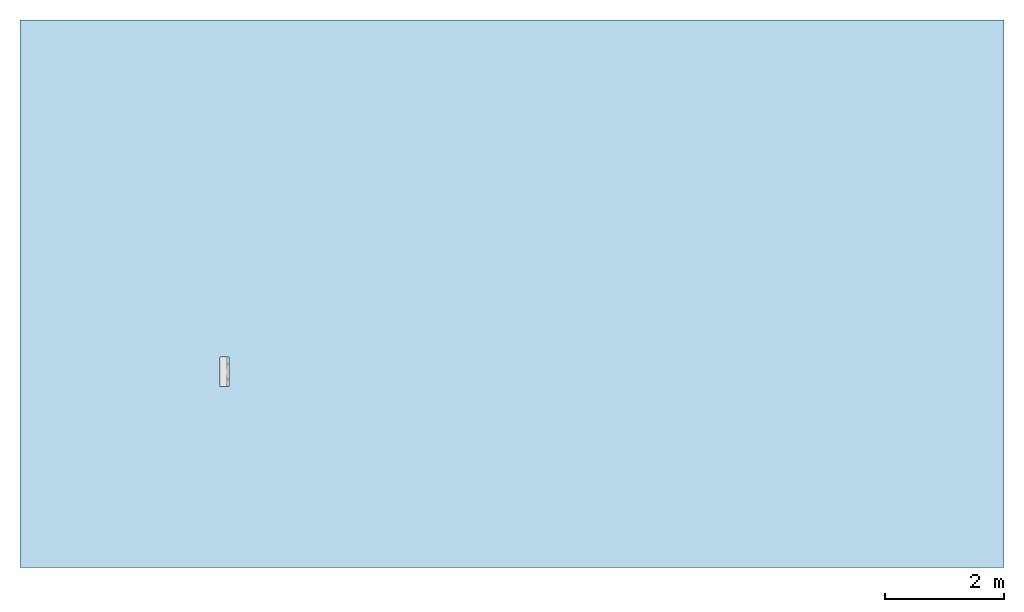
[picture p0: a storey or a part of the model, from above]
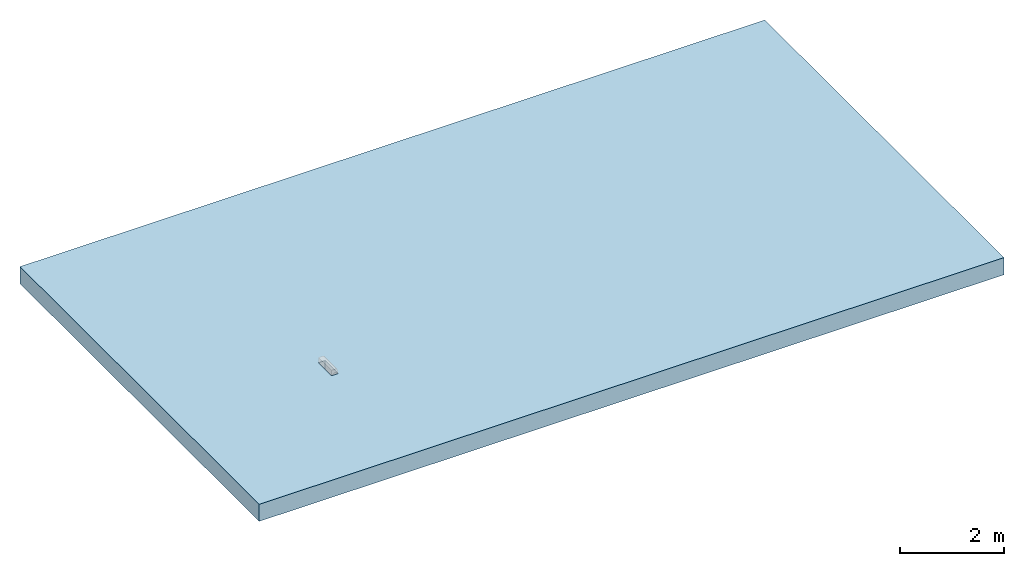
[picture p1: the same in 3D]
Properties of the parts of a building model (IFC2X3)

# File
Description: ViewDefinition [CoordinationView]
File name: 4231 - KDHB405 Channel - 500mm LG.ifc
Time: 2013-09-02T12:39:34
Written by: Autodesk Revit 2013
Made in: 20120221_2030(x64)

# IfcProject, Project Number
LongName: Project Name; Phase: Project Status

# IfcSite, Default
RefLatitude: 42, 21, 30, 344238; RefLongitude: -71, -3, -35, -194702; RefElevation: 0 mm

# IfcBuilding
Pset_BuildingCommon - NumberOfStoreys: 1
Other - Project Status: Project Status; Client Name: Owner; Project Number: Project Number; Project Address: ## Street City, State Zip; Project Name: Project Name; Project Issue Date: Issue Date

# IfcBuildingStorey, Level 1
LongName: Level 1; Elevation: 0 mm
Constraints - Elevation Base: 0; Elevation: 0 mm
Graphics - Line Pattern: Center; Symbol at End 2 Default: yes; Symbol: M_Level Head - Circle: M_Level Head - Circle; Color: 0; Line Weight: 1; Symbol at End 1 Default: no
Identity Data - Name: Level 1; Structural: no; Building Story: yes
Dimensions - Computation Height: 0 mm

# IfcBuildingElementProxy: 4231 - KDHB405 Channel - 500mm LG, Civil-Drainage-Channel-ACO-KerbDrain-HB405:4231 - KDHB405 Channel - 500mm LG:4231 - KDHB405 Channel - 500mm LG:312781
In: Level 1
Material: ACO Polymer Concrete.
Constraints - Level: Level: Level 1; Moves With Nearby Elements: no
Dimensions - Volume: 15413123 mm3; Void Width: 150 mm; Void Depth: -280 mm; Void Length: 500 mm; Circular Void Depth: 2000 mm
Phasing - Phase Created: New Construction
Pset_BuildingElementProxyCommon - Reference: 4231 - KDHB405 Channel - 500mm LG
Identity Data - e-mail Technical: technical@aco.co.uk; Model Description: Combined kerb and drainage system; Address: ACO Business Park, Hitchin Road, Shefford, Bedfordshire, United Kingdom SG17 5TE; Product Code: 4231; Product Page URL: http://www.aco.co.uk/product_detail.php?id=3; Assembly Description: Rain Water Drainage; Product brochure: http://www.aco.co.uk/download.php?id=120; Price: POA - contact ACO; Maintenance guidelines: http://www.aco.co.uk/download.php?id=120; Installation guidelines: http://www.aco.co.uk/download.php?id=120; URL: www.aco.co.uk; Type Comments: ACO KerbDrain HB405 half battered kerb unit 500mm long; Cost: 0; OmniClass Title: Rainwater Removal; Manufacturer: ACO Technologies plc - ACO Water Management Division; OmniClass Number: 23.70.50.24; e-mail Sales: customersupport@aco.co.uk; Telephone: +44 (0)1462 816666; Model: ACO KerbDrain HB405; Fax: +44 (0)1462 815895; Assembly Code: D2040
Construction - HB405 500_blindunit: no; RH drop kerb: no; LH drop kerb: no; Closing end cap: no; LH inlet/outlet end cap: no; RH inlet/outlet end cap: no; Access Unit: no; HB405 - 1000: no; HB405 - 500: yes; Centre Stone: no
Green Building Properties - Channel Recyclable: Fully recyclable; End Cap Recycled Material Content: N/A; Channel Recycled Material Content: 20% minimum; Access Cover/Frame Recycled Material Content: N/A; Access Cover/Frame Recyclable: N/A; End Cap Recyclable: N/A
General - SerialNumber: 0.000000; TagNumber: 0.000000
Materials and Finishes - Channel Colour: Grey; End Cap Colour: N/A; End Cap Material: N/A; Access Cover/Frame Finish: N/A; Connection Pipe Material: N/A; Channel Material: Vienite® Synthetic Resin Concrete; Access Cover/Frame Material: N/A; Connection Pipe Material Colour: N/A; Access Cover/Frame Colour: N/A
Data - Drainage Slot Intake area: 14592mm²/m; Product Dimensions: 500mm x 150mm x 405mm (LxWxH); Hydraulic Performance: http://www.aco.co.uk/download.php?id=120; Invert Depth: 380mm; Channel C.S.A: 0.03m²; Product Weight: 30.9 kg; Connection Pipe O.D: N/A; Concrete Surround Volume - Load Class A 15 - D 400 - Concrete Pavement: 0.17m³/m; Load Class: A 15 - D 400 A 15 - D 400; Drainage Slot Width: 50mm; Concrete Surround Volume - Load Class A 15 - D 400 - Grass or Asphalt Pavement: 0.16m³/m; ACO Hydraulic Design Software: http://www.acodesign.co.uk; Installation - Concrete Grade: Refer to brochure; Product Standard: BS EN 1433:2002, CE marked, Kitemarked
Other - CreatedBy: www.aco.co.uk; Revision: 1

# IfcOpeningElement: Recess (2)
In: Level 1
Constraints - Height Offset From Level: 0 mm; Room Bounding: yes; Related to Mass: no; Level: Level: Level 1
Dimensions - Thickness: 400 mm; Area: 151470000 mm2; Perimeter: 51360 mm; Volume: 60567000000 mm3
Structural - Structural: no; Enable Analytical Model: no
Phasing - Phase Created: New Construction
Construction - Default Thickness: 400 mm; Function: 0
Graphics - Coarse Scale Fill Color: 0
Analytical Properties - Absorptance: 0.1; Roughness: 1
Materials and Finishes - Structural Material: Plant

# IfcSlab: Floor:Generic Floor - 400mm, Floor:Generic Floor - 400mm:193825
In: Level 1
PredefinedType: FLOOR; Material: Plant 400 mm
Constraints - Height Offset From Level: 0 mm; Room Bounding: yes; Related to Mass: no; Level: Level: Level 1
Dimensions - Thickness: 400 mm; Area: 151470000 mm2; Perimeter: 51360 mm; Volume: 60567000000 mm3
Structural - Structural: no; Enable Analytical Model: no
Phasing - Phase Created: New Construction
Pset_SlabCommon - Reference: Generic Floor - 400mm; IsExternal: no; LoadBearing: yes
Construction - Default Thickness: 400 mm; Function: 0
Graphics - Coarse Scale Fill Color: 0
Analytical Properties - Absorptance: 0.1; Roughness: 1
Materials and Finishes - Structural Material: Plant
